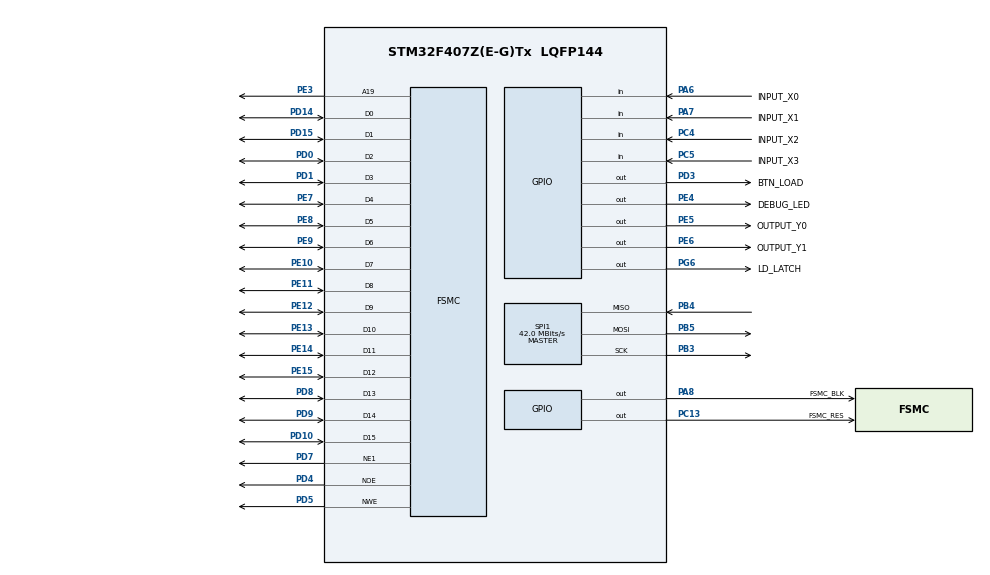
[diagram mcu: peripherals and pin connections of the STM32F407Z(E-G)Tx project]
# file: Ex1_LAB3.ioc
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FSMC.AddressSetupTime1=0xf
FSMC.BusTurnAroundDuration1=0
FSMC.DataSetupTime1=60
FSMC.ExtendedAddressSetupTime1=8
FSMC.ExtendedBusTurnAroundDuration1=0
FSMC.ExtendedDataSetupTime1=9
FSMC.ExtendedMode1=FSMC_EXTENDED_MODE_ENABLE
Mcu.Family=STM32F4
Mcu.Name=STM32F407Z(E-G)Tx
Mcu.Package=LQFP144
NVIC.PriorityGroup=NVIC_PRIORITYGROUP_4
NVIC.TIM2_IRQn=true\:0\:0\:false\:false\:true\:true\:true
PA13.Mode=Serial_Wire
PA13.Signal=SYS_JTMS-SWDIO
PA14.Mode=Serial_Wire
PA14.Signal=SYS_JTCK-SWCLK
PA6.GPIO_Label=INPUT_X0
PA6.Signal=GPIO_Input
PA7.GPIO_Label=INPUT_X1
PA7.Signal=GPIO_Input
PA8.GPIO_Label=FSMC_BLK
PA8.Signal=GPIO_Output
PB3.Mode=Full_Duplex_Master
PB3.Signal=SPI1_SCK
PB4.Mode=Full_Duplex_Master
PB4.Signal=SPI1_MISO
PB5.Mode=Full_Duplex_Master
PB5.Signal=SPI1_MOSI
PC13-ANTI_TAMP.GPIO_Label=FSMC_RES
PC13-ANTI_TAMP.Signal=GPIO_Output
PC4.GPIO_Label=INPUT_X2
PC4.Signal=GPIO_Input
PC5.GPIO_Label=INPUT_X3
PC5.Signal=GPIO_Input
PD0.Signal=FSMC_D2_DA2
PD1.Signal=FSMC_D3_DA3
PD10.Signal=FSMC_D15_DA15
PD14.Signal=FSMC_D0_DA0
PD15.Signal=FSMC_D1_DA1
PD3.GPIO_Label=BTN_LOAD
PD3.Signal=GPIO_Output
PD4.Signal=FSMC_NOE
PD5.Signal=FSMC_NWE
PD7.Mode=NorPsramChipSelect1_1
PD7.Signal=FSMC_NE1
PD8.Signal=FSMC_D13_DA13
PD9.Signal=FSMC_D14_DA14
PE10.Signal=FSMC_D7_DA7
PE11.Signal=FSMC_D8_DA8
PE12.Signal=FSMC_D9_DA9
PE13.Signal=FSMC_D10_DA10
PE14.Signal=FSMC_D11_DA11
PE15.Signal=FSMC_D12_DA12
PE3.Signal=FSMC_A19
PE4.GPIO_Label=DEBUG_LED
PE4.Signal=GPIO_Output
PE5.GPIO_Label=OUTPUT_Y0
PE5.Signal=GPIO_Output
PE6.GPIO_Label=OUTPUT_Y1
PE6.Signal=GPIO_Output
PE7.Signal=FSMC_D4_DA4
PE8.Signal=FSMC_D5_DA5
PE9.Signal=FSMC_D6_DA6
PG6.GPIO_Label=LD_LATCH
PG6.Signal=GPIO_Output
PH0-OSC_IN.Mode=HSE-External-Oscillator
PH0-OSC_IN.Signal=RCC_OSC_IN
PH1-OSC_OUT.Mode=HSE-External-Oscillator
PH1-OSC_OUT.Signal=RCC_OSC_OUT
ProjectManager.HeapSize=0x200
ProjectManager.StackSize=0x400
ProjectManager.TargetToolchain=STM32CubeIDE
RCC.48MHZClocksFreq_Value=84000000
RCC.AHBFreq_Value=168000000
RCC.APB1CLKDivider=RCC_HCLK_DIV4
RCC.APB1Freq_Value=42000000
RCC.APB1TimFreq_Value=84000000
RCC.APB2CLKDivider=RCC_HCLK_DIV2
RCC.APB2Freq_Value=84000000
RCC.APB2TimFreq_Value=168000000
RCC.CortexFreq_Value=168000000
RCC.HCLKFreq_Value=168000000
RCC.HSE_VALUE=8000000
RCC.HSI_VALUE=16000000
RCC.LSE_VALUE=32768
RCC.PLLM=8
RCC.PLLN=168
RCC.SYSCLKFreq_VALUE=168000000
RCC.SYSCLKSource=RCC_SYSCLKSOURCE_PLLCLK
RCC.VCOOutputFreq_Value=336000000
SH.FSMC_A19.0=FSMC_A19,A19_1
SH.FSMC_D0_DA0.0=FSMC_D0,16b-d1
SH.FSMC_D10_DA10.0=FSMC_D10,16b-d1
SH.FSMC_D11_DA11.0=FSMC_D11,16b-d1
SH.FSMC_D12_DA12.0=FSMC_D12,16b-d1
SH.FSMC_D13_DA13.0=FSMC_D13,16b-d1
SH.FSMC_D14_DA14.0=FSMC_D14,16b-d1
SH.FSMC_D15_DA15.0=FSMC_D15,16b-d1
SH.FSMC_D1_DA1.0=FSMC_D1,16b-d1
SH.FSMC_D2_DA2.0=FSMC_D2,16b-d1
SH.FSMC_D3_DA3.0=FSMC_D3,16b-d1
SH.FSMC_D4_DA4.0=FSMC_D4,16b-d1
SH.FSMC_D5_DA5.0=FSMC_D5,16b-d1
SH.FSMC_D6_DA6.0=FSMC_D6,16b-d1
SH.FSMC_D7_DA7.0=FSMC_D7,16b-d1
SH.FSMC_D8_DA8.0=FSMC_D8,16b-d1
SH.FSMC_D9_DA9.0=FSMC_D9,16b-d1
SH.FSMC_NOE.0=FSMC_NOE,Lcd1
SH.FSMC_NWE.0=FSMC_NWE,Lcd1
SPI1.CalculateBaudRate=42.0 MBits/s
SPI1.Direction=SPI_DIRECTION_2LINES
SPI1.Mode=SPI_MODE_MASTER
SPI1.VirtualType=VM_MASTER
TIM2.Period=100-1
TIM2.Prescaler=840-1
VP_TIM2_VS_ClockSourceINT.Mode=Internal
board=custom

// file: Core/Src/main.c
/* USER CODE BEGIN Header */
/**
  ******************************************************************************
  * @file           : main.c
  * @brief          : Main program body
  ******************************************************************************
  * @attention
  *
  * <h2><center>&copy; Copyright (c) 2023 STMicroelectronics.
  * All rights reserved.</center></h2>
  *
  * This software component is licensed by ST under BSD 3-Clause license,
  * the "License"; You may not use this file except in compliance with the
  * License. You may obtain a copy of the License at:
  *                        opensource.org/licenses/BSD-3-Clause
  *
  ******************************************************************************
  */
/* USER CODE END Header */
#include "main.h"
#include "spi.h"
#include "tim.h"
#include "gpio.h"
#include "fsmc.h"

/* USER CODE BEGIN Includes */
#include "software_timer.h"
#include "led_7seg.h"
#include "button.h"
#include "lcd.h"
#include "picture.h"
/* USER CODE END Includes */

/* USER CODE BEGIN PV */
uint8_t hours = 12;
uint8_t minutes = 0;
uint8_t colon_state = 0;
/* USER CODE END PV */

void SystemClock_Config(void);
/* USER CODE BEGIN PFP */
void system_init();
void update_time();
void display_time();
/* USER CODE END PFP */

int main(void)
{

  /* MCU Configuration--------------------------------------------------------*/

  /* Reset of all peripherals, Initializes the Flash interface and the Systick. */
  HAL_Init();

  /* Configure the system clock */
  SystemClock_Config();

  /* Initialize all configured peripherals */
  MX_GPIO_Init();
  MX_TIM2_Init();
  MX_SPI1_Init();
  MX_FSMC_Init();
  /* USER CODE BEGIN 2 */
  system_init();
  /* USER CODE END 2 */

  /* Infinite loop */
  /* USER CODE BEGIN WHILE */
  uint16_t counter = 0;
  while (1)
  {
	  	  while (!flag_timer2);
	      flag_timer2 = 0;
	      display_time();
	      counter++;
	      if (counter == 1200) { // 1 phút
	          update_time();
	      } else if (counter == 2400) { // 2phust
	    	  counter = 0;
	    	  update_time();
	    	  colon_state = !colon_state;
	      }

    /* USER CODE END WHILE */

  }
}

void SystemClock_Config(void)
{
  RCC_OscInitTypeDef RCC_OscInitStruct = {0};
  RCC_ClkInitTypeDef RCC_ClkInitStruct = {0};

  /** Configure the main internal regulator output voltage
  */
  __HAL_RCC_PWR_CLK_ENABLE();
  __HAL_PWR_VOLTAGESCALING_CONFIG(PWR_REGULATOR_VOLTAGE_SCALE1);
  /** Initializes the RCC Oscillators according to the specified parameters
  * in the RCC_OscInitTypeDef structure.
  */
  RCC_OscInitStruct.OscillatorType = RCC_OSCILLATORTYPE_HSI;
  RCC_OscInitStruct.HSIState = RCC_HSI_ON;
  RCC_OscInitStruct.HSICalibrationValue = RCC_HSICALIBRATION_DEFAULT;
  RCC_OscInitStruct.PLL.PLLState = RCC_PLL_ON;
  RCC_OscInitStruct.PLL.PLLSource = RCC_PLLSOURCE_HSI;
  RCC_OscInitStruct.PLL.PLLM = 8;
  RCC_OscInitStruct.PLL.PLLN = 168;
  RCC_OscInitStruct.PLL.PLLP = RCC_PLLP_DIV2;
  RCC_OscInitStruct.PLL.PLLQ = 4;
  if (HAL_RCC_OscConfig(&RCC_OscInitStruct) != HAL_OK)
  {
    Error_Handler();
  }
  /** Initializes the CPU, AHB and APB buses clocks
  */
  RCC_ClkInitStruct.ClockType = RCC_CLOCKTYPE_HCLK|RCC_CLOCKTYPE_SYSCLK
                              |RCC_CLOCKTYPE_PCLK1|RCC_CLOCKTYPE_PCLK2;
  RCC_ClkInitStruct.SYSCLKSource = RCC_SYSCLKSOURCE_PLLCLK;
  RCC_ClkInitStruct.AHBCLKDivider = RCC_SYSCLK_DIV1;
  RCC_ClkInitStruct.APB1CLKDivider = RCC_HCLK_DIV4;
  RCC_ClkInitStruct.APB2CLKDivider = RCC_HCLK_DIV4;

  if (HAL_RCC_ClockConfig(&RCC_ClkInitStruct, FLASH_LATENCY_5) != HAL_OK)
  {
    Error_Handler();
  }
}

/* USER CODE BEGIN 4 */
void system_init(){
	  timer_init();
	  led7_init();
	  setTimer2(50);
}
void update_time() {
    minutes++;
    if (minutes >= 60) {
        minutes = 0;
        hours++;
        if (hours >= 24) {
            hours = 0;
        }
    }
}
void display_time() {
    led7_SetDigit(hours / 10, 0, 0); // Hàng chục của giờ
    led7_SetDigit(hours % 10, 1, 0); // Hàng đơn vị của giờ
    led7_SetDigit(minutes / 10, 2, 0); // Hàng chục của phút
    led7_SetDigit(minutes % 10, 3, 0); // Hàng đơn vị của phút
    // Điều khiển dấu hai chấm chớp tắt
    led7_SetColon(colon_state);
}

/* USER CODE END 4 */

void Error_Handler(void)
{
  __disable_irq();
  while (1)
  {
  }
}

/************************ (C) COPYRIGHT STMicroelectronics *****END OF FILE****/
